VERSION 5.7 ;
  NOWIREEXTENSIONATPIN ON ;
  DIVIDERCHAR "/" ;
  BUSBITCHARS "[]" ;
MACRO INV_4_0_0_1653188215
  CLASS BLOCK ;
  FOREIGN INV_4_0_0_1653188215 ;
  ORIGIN 0.000 0.000 ;
  SIZE 5.415 BY 7.560 ;
  OBS
      LAYER nwell ;
        RECT 0.000 0.000 3.440 7.560 ;
      LAYER pwell ;
        RECT 4.515 6.030 4.945 7.410 ;
        RECT 4.045 2.180 5.415 3.490 ;
      LAYER li1 ;
        RECT 1.165 6.215 1.415 7.225 ;
        RECT 2.025 6.215 2.275 7.225 ;
        RECT 4.605 6.215 4.855 7.225 ;
        RECT 1.165 4.115 1.415 5.125 ;
        RECT 2.025 4.115 2.275 5.125 ;
        RECT 4.605 4.115 4.855 5.125 ;
        RECT 0.735 0.335 0.985 3.865 ;
        RECT 1.165 0.335 1.415 3.865 ;
        RECT 1.595 0.335 1.845 3.865 ;
        RECT 2.025 0.335 2.275 3.865 ;
        RECT 2.455 0.335 2.705 3.865 ;
        RECT 4.175 0.335 4.425 3.865 ;
        RECT 4.605 0.335 4.855 3.865 ;
        RECT 5.035 0.335 5.285 3.865 ;
      LAYER mcon ;
        RECT 1.205 6.635 1.375 6.805 ;
        RECT 2.065 6.635 2.235 6.805 ;
        RECT 4.645 6.635 4.815 6.805 ;
        RECT 1.205 4.535 1.375 4.705 ;
        RECT 2.065 4.535 2.235 4.705 ;
        RECT 4.645 4.535 4.815 4.705 ;
        RECT 0.775 0.755 0.945 0.925 ;
        RECT 1.205 0.335 1.375 0.505 ;
        RECT 1.635 0.755 1.805 0.925 ;
        RECT 2.065 0.335 2.235 0.505 ;
        RECT 2.495 0.755 2.665 0.925 ;
        RECT 4.215 0.755 4.385 0.925 ;
        RECT 4.645 0.335 4.815 0.505 ;
        RECT 5.075 0.755 5.245 0.925 ;
      LAYER met1 ;
        RECT 1.120 6.580 2.320 6.860 ;
        RECT 3.700 6.580 4.900 6.860 ;
        RECT 1.120 4.480 4.900 4.760 ;
        RECT 0.690 0.700 2.750 0.980 ;
        RECT 4.130 0.700 5.330 0.980 ;
        RECT 1.120 0.280 4.900 0.560 ;
  END
END INV_4_0_0_1653188215
MACRO INV_4_1_0_1653188216
  CLASS BLOCK ;
  FOREIGN INV_4_1_0_1653188216 ;
  ORIGIN 0.000 0.000 ;
  SIZE 5.415 BY 7.560 ;
  OBS
      LAYER nwell ;
        RECT 0.000 0.000 3.440 7.560 ;
      LAYER pwell ;
        RECT 4.515 6.030 4.945 7.410 ;
        RECT 4.045 2.180 5.415 3.490 ;
      LAYER li1 ;
        RECT 1.165 6.215 1.415 7.225 ;
        RECT 2.025 6.215 2.275 7.225 ;
        RECT 4.605 6.215 4.855 7.225 ;
        RECT 1.165 4.115 1.415 5.125 ;
        RECT 2.025 4.115 2.275 5.125 ;
        RECT 4.605 4.115 4.855 5.125 ;
        RECT 0.735 0.335 0.985 3.865 ;
        RECT 1.165 0.335 1.415 3.865 ;
        RECT 1.595 0.335 1.845 3.865 ;
        RECT 2.025 0.335 2.275 3.865 ;
        RECT 2.455 0.335 2.705 3.865 ;
        RECT 4.175 0.335 4.425 3.865 ;
        RECT 4.605 0.335 4.855 3.865 ;
        RECT 5.035 0.335 5.285 3.865 ;
      LAYER mcon ;
        RECT 1.205 6.635 1.375 6.805 ;
        RECT 2.065 6.635 2.235 6.805 ;
        RECT 4.645 6.635 4.815 6.805 ;
        RECT 1.205 4.535 1.375 4.705 ;
        RECT 2.065 4.535 2.235 4.705 ;
        RECT 4.645 4.535 4.815 4.705 ;
        RECT 0.775 0.755 0.945 0.925 ;
        RECT 1.205 0.335 1.375 0.505 ;
        RECT 1.635 0.755 1.805 0.925 ;
        RECT 2.065 0.335 2.235 0.505 ;
        RECT 2.495 0.755 2.665 0.925 ;
        RECT 4.215 0.755 4.385 0.925 ;
        RECT 4.645 0.335 4.815 0.505 ;
        RECT 5.075 0.755 5.245 0.925 ;
      LAYER met1 ;
        RECT 1.120 6.580 2.320 6.860 ;
        RECT 3.700 6.580 4.900 6.860 ;
        RECT 1.120 4.480 4.900 4.760 ;
        RECT 0.690 0.700 2.750 0.980 ;
        RECT 4.130 0.700 5.330 0.980 ;
        RECT 1.120 0.280 4.900 0.560 ;
  END
END INV_4_1_0_1653188216
MACRO DCDC_MUX_PMOS_0_0_1653188212
  CLASS BLOCK ;
  FOREIGN DCDC_MUX_PMOS_0_0_1653188212 ;
  ORIGIN 0.000 0.160 ;
  SIZE 8.600 BY 7.720 ;
  OBS
      LAYER nwell ;
        RECT 0.000 0.000 8.600 7.560 ;
      LAYER li1 ;
        RECT 1.165 6.215 1.415 7.225 ;
        RECT 2.025 6.215 2.275 7.225 ;
        RECT 2.885 6.215 3.135 7.225 ;
        RECT 5.465 6.215 5.715 7.225 ;
        RECT 6.325 6.215 6.575 7.225 ;
        RECT 7.185 6.215 7.435 7.225 ;
        RECT 1.165 4.115 1.415 5.125 ;
        RECT 2.025 4.115 2.275 5.125 ;
        RECT 2.885 4.115 3.135 5.125 ;
        RECT 5.465 4.115 5.715 5.125 ;
        RECT 6.325 4.115 6.575 5.125 ;
        RECT 7.185 4.115 7.435 5.125 ;
        RECT 0.735 0.335 0.985 3.865 ;
        RECT 1.165 0.335 1.415 3.865 ;
        RECT 1.595 0.335 1.845 3.865 ;
        RECT 2.025 0.335 2.275 3.865 ;
        RECT 2.455 0.335 2.705 3.865 ;
        RECT 2.885 0.335 3.135 3.865 ;
        RECT 3.315 0.335 3.565 3.865 ;
        RECT 4.175 0.335 4.425 0.925 ;
        RECT 5.035 0.335 5.285 3.865 ;
        RECT 5.465 0.335 5.715 3.865 ;
        RECT 5.895 0.335 6.145 3.865 ;
        RECT 6.325 0.335 6.575 3.865 ;
        RECT 6.755 0.335 7.005 3.865 ;
        RECT 7.185 0.335 7.435 3.865 ;
        RECT 7.615 0.335 7.865 3.865 ;
      LAYER mcon ;
        RECT 1.205 6.635 1.375 6.805 ;
        RECT 2.065 6.635 2.235 6.805 ;
        RECT 2.925 6.635 3.095 6.805 ;
        RECT 5.505 6.635 5.675 6.805 ;
        RECT 6.365 6.635 6.535 6.805 ;
        RECT 7.225 6.635 7.395 6.805 ;
        RECT 1.205 4.535 1.375 4.705 ;
        RECT 2.065 4.535 2.235 4.705 ;
        RECT 2.925 4.535 3.095 4.705 ;
        RECT 5.505 4.535 5.675 4.705 ;
        RECT 6.365 4.535 6.535 4.705 ;
        RECT 7.225 4.535 7.395 4.705 ;
        RECT 0.775 0.755 0.945 0.925 ;
        RECT 1.205 0.335 1.375 0.505 ;
        RECT 1.635 0.755 1.805 0.925 ;
        RECT 2.065 0.335 2.235 0.505 ;
        RECT 2.495 0.755 2.665 0.925 ;
        RECT 2.925 0.335 3.095 0.505 ;
        RECT 3.355 0.755 3.525 0.925 ;
        RECT 4.215 0.755 4.385 0.925 ;
        RECT 4.215 0.335 4.385 0.505 ;
        RECT 5.075 0.755 5.245 0.925 ;
        RECT 5.505 0.335 5.675 0.505 ;
        RECT 5.935 0.755 6.105 0.925 ;
        RECT 6.365 0.335 6.535 0.505 ;
        RECT 6.795 0.755 6.965 0.925 ;
        RECT 7.225 0.335 7.395 0.505 ;
        RECT 7.655 0.755 7.825 0.925 ;
      LAYER met1 ;
        RECT 1.120 6.580 7.480 6.860 ;
        RECT 1.120 4.480 3.180 4.760 ;
        RECT 5.420 4.480 7.480 4.760 ;
        RECT 0.690 0.700 4.470 0.980 ;
        RECT 4.990 0.700 7.910 0.980 ;
        RECT 1.120 0.280 3.600 0.560 ;
        RECT 4.130 0.280 7.480 0.560 ;
        RECT 3.280 -0.140 5.320 0.140 ;
      LAYER via ;
        RECT 5.030 0.710 5.290 0.970 ;
        RECT 3.310 0.290 3.570 0.550 ;
        RECT 3.310 -0.130 3.570 0.130 ;
        RECT 5.030 -0.130 5.290 0.130 ;
      LAYER met2 ;
        RECT 3.300 -0.160 3.580 0.580 ;
        RECT 5.020 -0.160 5.300 1.000 ;
  END
END DCDC_MUX_PMOS_0_0_1653188212
MACRO DCDC_MUX_TGATE_0_0_1653188213
  CLASS BLOCK ;
  FOREIGN DCDC_MUX_TGATE_0_0_1653188213 ;
  ORIGIN 0.000 -0.150 ;
  SIZE 4.300 BY 14.970 ;
  OBS
      LAYER nwell ;
        RECT 0.000 7.560 4.300 15.120 ;
      LAYER pwell ;
        RECT 0.605 4.070 3.695 5.380 ;
        RECT 1.075 0.150 3.225 1.530 ;
      LAYER li1 ;
        RECT 1.165 13.775 1.415 14.785 ;
        RECT 2.025 13.775 2.275 14.785 ;
        RECT 2.885 13.775 3.135 14.785 ;
        RECT 1.165 11.675 1.415 12.685 ;
        RECT 2.025 11.675 2.275 12.685 ;
        RECT 2.885 11.675 3.135 12.685 ;
        RECT 0.735 7.895 0.985 11.425 ;
        RECT 1.165 7.895 1.415 11.425 ;
        RECT 1.595 7.895 1.845 11.425 ;
        RECT 2.025 7.895 2.275 11.425 ;
        RECT 2.455 7.895 2.705 11.425 ;
        RECT 2.885 7.895 3.135 11.425 ;
        RECT 3.315 7.895 3.565 11.425 ;
        RECT 0.735 3.695 0.985 7.225 ;
        RECT 1.165 3.695 1.415 7.225 ;
        RECT 1.595 3.695 1.845 7.225 ;
        RECT 2.025 3.695 2.275 7.225 ;
        RECT 2.455 3.695 2.705 7.225 ;
        RECT 2.885 3.695 3.135 7.225 ;
        RECT 3.315 3.695 3.565 7.225 ;
        RECT 1.165 2.435 1.415 3.445 ;
        RECT 2.025 2.435 2.275 3.445 ;
        RECT 2.885 2.435 3.135 3.445 ;
        RECT 1.165 0.335 1.415 1.345 ;
        RECT 2.025 0.335 2.275 1.345 ;
        RECT 2.885 0.335 3.135 1.345 ;
      LAYER mcon ;
        RECT 1.205 14.195 1.375 14.365 ;
        RECT 2.065 14.195 2.235 14.365 ;
        RECT 2.925 14.195 3.095 14.365 ;
        RECT 1.205 12.095 1.375 12.265 ;
        RECT 2.065 12.095 2.235 12.265 ;
        RECT 2.925 12.095 3.095 12.265 ;
        RECT 0.775 8.315 0.945 8.485 ;
        RECT 1.205 7.895 1.375 8.065 ;
        RECT 1.635 8.315 1.805 8.485 ;
        RECT 2.065 7.895 2.235 8.065 ;
        RECT 2.495 8.315 2.665 8.485 ;
        RECT 2.925 7.895 3.095 8.065 ;
        RECT 3.355 8.315 3.525 8.485 ;
        RECT 0.775 6.635 0.945 6.805 ;
        RECT 1.205 7.055 1.375 7.225 ;
        RECT 1.635 6.635 1.805 6.805 ;
        RECT 2.065 7.055 2.235 7.225 ;
        RECT 2.495 6.635 2.665 6.805 ;
        RECT 2.925 7.055 3.095 7.225 ;
        RECT 3.355 6.635 3.525 6.805 ;
        RECT 1.205 2.855 1.375 3.025 ;
        RECT 2.065 2.855 2.235 3.025 ;
        RECT 2.925 2.855 3.095 3.025 ;
        RECT 1.205 0.755 1.375 0.925 ;
        RECT 2.065 0.755 2.235 0.925 ;
        RECT 2.925 0.755 3.095 0.925 ;
      LAYER met1 ;
        RECT 1.120 14.140 3.180 14.420 ;
        RECT 1.120 12.040 3.180 12.320 ;
        RECT 0.690 8.260 3.610 8.540 ;
        RECT 1.120 7.840 3.180 8.120 ;
        RECT 1.120 7.000 3.180 7.280 ;
        RECT 0.690 6.580 3.610 6.860 ;
        RECT 1.120 2.800 3.180 3.080 ;
        RECT 1.120 0.700 3.180 0.980 ;
      LAYER via ;
        RECT 1.590 8.270 1.850 8.530 ;
        RECT 2.020 7.850 2.280 8.110 ;
        RECT 2.020 7.010 2.280 7.270 ;
        RECT 1.590 6.590 1.850 6.850 ;
      LAYER met2 ;
        RECT 1.580 6.560 1.860 8.560 ;
        RECT 2.010 6.980 2.290 8.140 ;
  END
END DCDC_MUX_TGATE_0_0_1653188213
MACRO DCDC_MUX_TGATE_1_0_1653188214
  CLASS BLOCK ;
  FOREIGN DCDC_MUX_TGATE_1_0_1653188214 ;
  ORIGIN 0.000 -0.150 ;
  SIZE 4.300 BY 14.970 ;
  OBS
      LAYER nwell ;
        RECT 0.000 7.560 4.300 15.120 ;
      LAYER pwell ;
        RECT 0.605 4.070 3.695 5.380 ;
        RECT 1.075 0.150 3.225 1.530 ;
      LAYER li1 ;
        RECT 1.165 13.775 1.415 14.785 ;
        RECT 2.025 13.775 2.275 14.785 ;
        RECT 2.885 13.775 3.135 14.785 ;
        RECT 1.165 11.675 1.415 12.685 ;
        RECT 2.025 11.675 2.275 12.685 ;
        RECT 2.885 11.675 3.135 12.685 ;
        RECT 0.735 7.895 0.985 11.425 ;
        RECT 1.165 7.895 1.415 11.425 ;
        RECT 1.595 7.895 1.845 11.425 ;
        RECT 2.025 7.895 2.275 11.425 ;
        RECT 2.455 7.895 2.705 11.425 ;
        RECT 2.885 7.895 3.135 11.425 ;
        RECT 3.315 7.895 3.565 11.425 ;
        RECT 0.735 3.695 0.985 7.225 ;
        RECT 1.165 3.695 1.415 7.225 ;
        RECT 1.595 3.695 1.845 7.225 ;
        RECT 2.025 3.695 2.275 7.225 ;
        RECT 2.455 3.695 2.705 7.225 ;
        RECT 2.885 3.695 3.135 7.225 ;
        RECT 3.315 3.695 3.565 7.225 ;
        RECT 1.165 2.435 1.415 3.445 ;
        RECT 2.025 2.435 2.275 3.445 ;
        RECT 2.885 2.435 3.135 3.445 ;
        RECT 1.165 0.335 1.415 1.345 ;
        RECT 2.025 0.335 2.275 1.345 ;
        RECT 2.885 0.335 3.135 1.345 ;
      LAYER mcon ;
        RECT 1.205 14.195 1.375 14.365 ;
        RECT 2.065 14.195 2.235 14.365 ;
        RECT 2.925 14.195 3.095 14.365 ;
        RECT 1.205 12.095 1.375 12.265 ;
        RECT 2.065 12.095 2.235 12.265 ;
        RECT 2.925 12.095 3.095 12.265 ;
        RECT 0.775 8.315 0.945 8.485 ;
        RECT 1.205 7.895 1.375 8.065 ;
        RECT 1.635 8.315 1.805 8.485 ;
        RECT 2.065 7.895 2.235 8.065 ;
        RECT 2.495 8.315 2.665 8.485 ;
        RECT 2.925 7.895 3.095 8.065 ;
        RECT 3.355 8.315 3.525 8.485 ;
        RECT 0.775 6.635 0.945 6.805 ;
        RECT 1.205 7.055 1.375 7.225 ;
        RECT 1.635 6.635 1.805 6.805 ;
        RECT 2.065 7.055 2.235 7.225 ;
        RECT 2.495 6.635 2.665 6.805 ;
        RECT 2.925 7.055 3.095 7.225 ;
        RECT 3.355 6.635 3.525 6.805 ;
        RECT 1.205 2.855 1.375 3.025 ;
        RECT 2.065 2.855 2.235 3.025 ;
        RECT 2.925 2.855 3.095 3.025 ;
        RECT 1.205 0.755 1.375 0.925 ;
        RECT 2.065 0.755 2.235 0.925 ;
        RECT 2.925 0.755 3.095 0.925 ;
      LAYER met1 ;
        RECT 1.120 14.140 3.180 14.420 ;
        RECT 1.120 12.040 3.180 12.320 ;
        RECT 0.690 8.260 3.610 8.540 ;
        RECT 1.120 7.840 3.180 8.120 ;
        RECT 1.120 7.000 3.180 7.280 ;
        RECT 0.690 6.580 3.610 6.860 ;
        RECT 1.120 2.800 3.180 3.080 ;
        RECT 1.120 0.700 3.180 0.980 ;
      LAYER via ;
        RECT 2.450 8.270 2.710 8.530 ;
        RECT 2.020 7.850 2.280 8.110 ;
        RECT 2.020 7.010 2.280 7.270 ;
        RECT 2.450 6.590 2.710 6.850 ;
      LAYER met2 ;
        RECT 2.010 6.980 2.290 8.140 ;
        RECT 2.440 6.560 2.720 8.560 ;
  END
END DCDC_MUX_TGATE_1_0_1653188214
MACRO DCDC_MUX_NMOS_0_0_1653188211
  CLASS BLOCK ;
  FOREIGN DCDC_MUX_NMOS_0_0_1653188211 ;
  ORIGIN -0.605 -0.260 ;
  SIZE 7.390 BY 7.150 ;
  OBS
      LAYER pwell ;
        RECT 1.075 6.030 3.225 7.410 ;
        RECT 5.375 6.030 7.525 7.410 ;
        RECT 0.605 2.180 3.695 3.490 ;
        RECT 4.905 2.180 7.995 3.490 ;
      LAYER li1 ;
        RECT 1.165 6.215 1.415 7.225 ;
        RECT 2.025 6.215 2.275 7.225 ;
        RECT 2.885 6.215 3.135 7.225 ;
        RECT 5.465 6.215 5.715 7.225 ;
        RECT 6.325 6.215 6.575 7.225 ;
        RECT 7.185 6.215 7.435 7.225 ;
        RECT 1.165 4.115 1.415 5.125 ;
        RECT 2.025 4.115 2.275 5.125 ;
        RECT 2.885 4.115 3.135 5.125 ;
        RECT 5.465 4.115 5.715 5.125 ;
        RECT 6.325 4.115 6.575 5.125 ;
        RECT 7.185 4.115 7.435 5.125 ;
        RECT 0.735 0.335 0.985 3.865 ;
        RECT 1.165 0.335 1.415 3.865 ;
        RECT 1.595 0.335 1.845 3.865 ;
        RECT 2.025 0.335 2.275 3.865 ;
        RECT 2.455 0.335 2.705 3.865 ;
        RECT 2.885 0.335 3.135 3.865 ;
        RECT 3.315 0.335 3.565 3.865 ;
        RECT 4.175 0.335 4.425 0.925 ;
        RECT 5.035 0.335 5.285 3.865 ;
        RECT 5.465 0.335 5.715 3.865 ;
        RECT 5.895 0.335 6.145 3.865 ;
        RECT 6.325 0.335 6.575 3.865 ;
        RECT 6.755 0.335 7.005 3.865 ;
        RECT 7.185 0.335 7.435 3.865 ;
        RECT 7.615 0.335 7.865 3.865 ;
      LAYER mcon ;
        RECT 1.205 6.635 1.375 6.805 ;
        RECT 2.065 6.635 2.235 6.805 ;
        RECT 2.925 6.635 3.095 6.805 ;
        RECT 5.505 6.635 5.675 6.805 ;
        RECT 6.365 6.635 6.535 6.805 ;
        RECT 7.225 6.635 7.395 6.805 ;
        RECT 1.205 4.535 1.375 4.705 ;
        RECT 2.065 4.535 2.235 4.705 ;
        RECT 2.925 4.535 3.095 4.705 ;
        RECT 5.505 4.535 5.675 4.705 ;
        RECT 6.365 4.535 6.535 4.705 ;
        RECT 7.225 4.535 7.395 4.705 ;
        RECT 0.775 0.755 0.945 0.925 ;
        RECT 1.205 0.335 1.375 0.505 ;
        RECT 1.635 0.755 1.805 0.925 ;
        RECT 2.065 0.335 2.235 0.505 ;
        RECT 2.495 0.755 2.665 0.925 ;
        RECT 2.925 0.335 3.095 0.505 ;
        RECT 3.355 0.755 3.525 0.925 ;
        RECT 4.215 0.755 4.385 0.925 ;
        RECT 4.215 0.335 4.385 0.505 ;
        RECT 5.075 0.755 5.245 0.925 ;
        RECT 5.505 0.335 5.675 0.505 ;
        RECT 5.935 0.755 6.105 0.925 ;
        RECT 6.365 0.335 6.535 0.505 ;
        RECT 6.795 0.755 6.965 0.925 ;
        RECT 7.225 0.335 7.395 0.505 ;
        RECT 7.655 0.755 7.825 0.925 ;
      LAYER met1 ;
        RECT 1.120 6.580 7.480 6.860 ;
        RECT 1.120 4.480 3.180 4.760 ;
        RECT 5.420 4.480 7.480 4.760 ;
        RECT 3.280 1.120 5.320 1.400 ;
        RECT 0.690 0.700 4.470 0.980 ;
        RECT 4.990 0.700 7.910 0.980 ;
        RECT 1.120 0.280 3.600 0.560 ;
        RECT 4.130 0.280 7.480 0.560 ;
      LAYER via ;
        RECT 3.310 1.130 3.570 1.390 ;
        RECT 5.030 1.130 5.290 1.390 ;
        RECT 5.030 0.710 5.290 0.970 ;
        RECT 3.310 0.290 3.570 0.550 ;
      LAYER met2 ;
        RECT 3.300 0.260 3.580 1.420 ;
        RECT 5.020 0.680 5.300 1.420 ;
  END
END DCDC_MUX_NMOS_0_0_1653188211
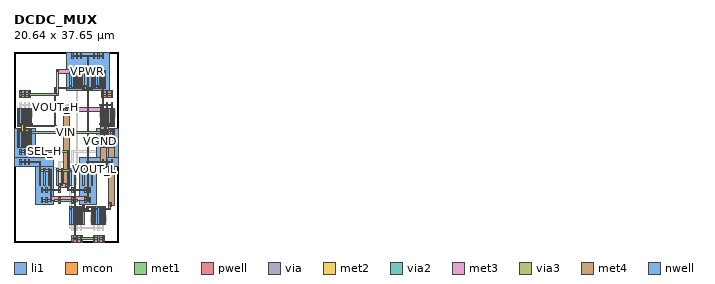
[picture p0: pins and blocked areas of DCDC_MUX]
MACRO DCDC_MUX
  CLASS BLOCK ;
  FOREIGN DCDC_MUX ;
  ORIGIN 0.000 -0.150 ;
  SIZE 20.640 BY 37.650 ;
  PIN SEL_H
    ANTENNAGATEAREA 1.890000 ;
    PORT
      LAYER li1 ;
        RECT 1.165 17.555 1.415 18.565 ;
        RECT 2.025 17.555 2.275 18.565 ;
        RECT 2.885 17.555 3.135 18.565 ;
        RECT 10.625 10.415 10.875 18.145 ;
        RECT 11.485 9.995 11.735 11.005 ;
        RECT 14.065 9.995 14.315 11.005 ;
        RECT 14.925 9.995 15.175 11.005 ;
      LAYER mcon ;
        RECT 1.205 17.975 1.375 18.145 ;
        RECT 2.065 17.975 2.235 18.145 ;
        RECT 2.925 17.975 3.095 18.145 ;
        RECT 10.665 17.975 10.835 18.145 ;
        RECT 10.665 10.415 10.835 10.585 ;
        RECT 11.525 10.415 11.695 10.585 ;
        RECT 14.105 10.415 14.275 10.585 ;
        RECT 14.965 10.415 15.135 10.585 ;
      LAYER met1 ;
        RECT 1.120 17.920 10.920 18.200 ;
        RECT 10.580 10.360 15.220 10.640 ;
    END
  END SEL_H
  PIN VGND
    USE GROUND ;
    PORT
      LAYER pwell ;
        RECT 1.075 28.710 3.225 30.090 ;
        RECT 17.415 28.710 19.565 30.090 ;
        RECT 8.815 7.710 9.245 9.090 ;
        RECT 11.395 7.710 11.825 9.090 ;
        RECT 11.395 0.150 13.545 1.530 ;
        RECT 15.695 0.150 17.845 1.530 ;
      LAYER li1 ;
        RECT 1.165 28.895 1.415 29.905 ;
        RECT 2.025 28.895 2.275 29.905 ;
        RECT 2.885 28.895 3.135 29.905 ;
        RECT 17.505 28.895 17.755 29.905 ;
        RECT 18.365 28.895 18.615 29.905 ;
        RECT 19.225 28.895 19.475 29.905 ;
        RECT 8.475 11.255 8.725 14.785 ;
        RECT 9.335 11.255 9.585 14.785 ;
        RECT 11.055 11.255 11.305 14.785 ;
        RECT 11.915 11.255 12.165 14.785 ;
        RECT 8.905 7.895 9.155 8.905 ;
        RECT 11.485 7.895 11.735 8.905 ;
        RECT 11.055 3.695 11.305 7.225 ;
        RECT 11.915 3.695 12.165 7.225 ;
        RECT 12.775 3.695 13.025 7.225 ;
        RECT 13.635 3.695 13.885 7.225 ;
        RECT 14.495 6.635 14.745 7.225 ;
        RECT 15.785 3.695 16.035 7.225 ;
        RECT 16.645 3.695 16.895 7.225 ;
        RECT 17.505 3.695 17.755 7.225 ;
        RECT 11.485 0.335 11.735 1.345 ;
        RECT 12.345 0.335 12.595 1.345 ;
        RECT 13.205 0.335 13.455 1.345 ;
        RECT 15.785 0.335 16.035 1.345 ;
        RECT 16.645 0.335 16.895 1.345 ;
        RECT 17.505 0.335 17.755 1.345 ;
      LAYER mcon ;
        RECT 1.205 29.315 1.375 29.485 ;
        RECT 2.065 29.315 2.235 29.485 ;
        RECT 2.925 29.315 3.095 29.485 ;
        RECT 17.545 29.315 17.715 29.485 ;
        RECT 18.405 29.315 18.575 29.485 ;
        RECT 19.265 29.315 19.435 29.485 ;
        RECT 8.515 14.195 8.685 14.365 ;
        RECT 9.375 14.195 9.545 14.365 ;
        RECT 11.095 14.195 11.265 14.365 ;
        RECT 11.955 14.195 12.125 14.365 ;
        RECT 8.945 8.315 9.115 8.485 ;
        RECT 11.525 8.315 11.695 8.485 ;
        RECT 11.095 6.635 11.265 6.805 ;
        RECT 11.955 6.635 12.125 6.805 ;
        RECT 12.815 6.635 12.985 6.805 ;
        RECT 13.675 6.635 13.845 6.805 ;
        RECT 14.535 7.055 14.705 7.225 ;
        RECT 14.535 6.635 14.705 6.805 ;
        RECT 15.825 7.055 15.995 7.225 ;
        RECT 16.685 7.055 16.855 7.225 ;
        RECT 17.545 7.055 17.715 7.225 ;
        RECT 11.525 0.755 11.695 0.925 ;
        RECT 12.385 0.755 12.555 0.925 ;
        RECT 13.245 0.755 13.415 0.925 ;
        RECT 15.825 0.755 15.995 0.925 ;
        RECT 16.685 0.755 16.855 0.925 ;
        RECT 17.545 0.755 17.715 0.925 ;
      LAYER met1 ;
        RECT 1.120 29.260 8.760 29.540 ;
        RECT 17.460 29.260 19.520 29.540 ;
        RECT 8.430 14.140 12.210 14.420 ;
        RECT 8.000 8.260 12.640 8.540 ;
        RECT 14.450 7.000 17.800 7.280 ;
        RECT 11.010 6.580 14.790 6.860 ;
        RECT 11.440 0.700 17.800 0.980 ;
      LAYER via ;
        RECT 8.470 29.270 8.730 29.530 ;
        RECT 17.500 29.270 17.760 29.530 ;
        RECT 11.910 14.150 12.170 14.410 ;
        RECT 11.910 8.270 12.170 8.530 ;
        RECT 11.910 6.590 12.170 6.850 ;
        RECT 11.910 0.710 12.170 0.970 ;
      LAYER met2 ;
        RECT 8.460 29.240 8.740 34.205 ;
        RECT 17.490 25.015 17.770 34.205 ;
        RECT 11.900 0.680 12.180 15.305 ;
      LAYER via2 ;
        RECT 8.460 33.880 8.740 34.160 ;
        RECT 17.490 33.880 17.770 34.160 ;
        RECT 17.490 25.060 17.770 25.340 ;
        RECT 11.900 14.980 12.180 15.260 ;
      LAYER met3 ;
        RECT 8.435 33.620 17.795 34.420 ;
        RECT 17.465 24.800 17.925 25.600 ;
        RECT 11.875 14.720 17.925 15.520 ;
      LAYER via3 ;
        RECT 17.600 25.040 17.920 25.360 ;
        RECT 17.600 14.960 17.920 15.280 ;
      LAYER met4 ;
        RECT 17.170 14.955 18.350 25.365 ;
    END
  END VGND
  PIN VPWR
    USE POWER ;
    PORT
      LAYER nwell ;
        RECT 10.320 30.240 18.920 37.800 ;
        RECT 0.000 16.800 4.300 22.680 ;
        RECT 16.340 16.800 20.640 22.680 ;
        RECT 0.000 15.120 7.740 16.800 ;
        RECT 4.300 7.560 7.740 15.120 ;
        RECT 12.900 15.120 20.640 16.800 ;
        RECT 12.900 7.560 16.340 15.120 ;
      LAYER li1 ;
        RECT 11.485 36.455 11.735 37.465 ;
        RECT 12.345 36.455 12.595 37.465 ;
        RECT 13.205 36.455 13.455 37.465 ;
        RECT 11.055 30.575 11.305 34.105 ;
        RECT 11.915 30.575 12.165 34.105 ;
        RECT 12.775 30.575 13.025 34.105 ;
        RECT 13.635 30.575 13.885 34.105 ;
        RECT 1.165 15.455 1.415 16.465 ;
        RECT 2.025 15.455 2.275 16.465 ;
        RECT 2.885 15.455 3.135 16.465 ;
        RECT 14.495 15.035 14.745 37.045 ;
        RECT 15.785 36.455 16.035 37.465 ;
        RECT 16.645 36.455 16.895 37.465 ;
        RECT 17.505 36.455 17.755 37.465 ;
        RECT 15.785 30.575 16.035 34.105 ;
        RECT 16.645 30.575 16.895 34.105 ;
        RECT 17.505 30.575 17.755 34.105 ;
        RECT 17.505 15.455 17.755 16.465 ;
        RECT 18.365 15.455 18.615 16.465 ;
        RECT 19.225 15.455 19.475 16.465 ;
        RECT 5.035 11.255 5.285 14.785 ;
        RECT 5.895 11.255 6.145 14.785 ;
        RECT 6.755 11.255 7.005 14.785 ;
        RECT 13.635 11.255 13.885 14.785 ;
        RECT 14.495 11.255 14.745 14.785 ;
        RECT 15.355 11.255 15.605 14.785 ;
        RECT 5.465 7.895 5.715 8.905 ;
        RECT 6.325 7.895 6.575 8.905 ;
        RECT 14.065 7.895 14.315 8.905 ;
        RECT 14.925 7.895 15.175 8.905 ;
      LAYER mcon ;
        RECT 11.525 36.875 11.695 37.045 ;
        RECT 12.385 36.875 12.555 37.045 ;
        RECT 13.245 36.875 13.415 37.045 ;
        RECT 14.535 36.875 14.705 37.045 ;
        RECT 11.095 30.995 11.265 31.165 ;
        RECT 11.955 30.995 12.125 31.165 ;
        RECT 12.815 30.995 12.985 31.165 ;
        RECT 13.675 30.995 13.845 31.165 ;
        RECT 15.825 36.875 15.995 37.045 ;
        RECT 16.685 36.875 16.855 37.045 ;
        RECT 17.545 36.875 17.715 37.045 ;
        RECT 14.535 30.995 14.705 31.165 ;
        RECT 14.535 30.575 14.705 30.745 ;
        RECT 15.825 30.575 15.995 30.745 ;
        RECT 16.685 30.575 16.855 30.745 ;
        RECT 17.545 30.575 17.715 30.745 ;
        RECT 1.205 15.875 1.375 16.045 ;
        RECT 2.065 15.875 2.235 16.045 ;
        RECT 2.925 15.875 3.095 16.045 ;
        RECT 14.535 15.875 14.705 16.045 ;
        RECT 17.545 15.875 17.715 16.045 ;
        RECT 18.405 15.875 18.575 16.045 ;
        RECT 19.265 15.875 19.435 16.045 ;
        RECT 14.535 15.035 14.705 15.205 ;
        RECT 5.075 14.195 5.245 14.365 ;
        RECT 5.935 14.195 6.105 14.365 ;
        RECT 6.795 14.195 6.965 14.365 ;
        RECT 13.675 14.195 13.845 14.365 ;
        RECT 14.535 14.195 14.705 14.365 ;
        RECT 15.395 14.195 15.565 14.365 ;
        RECT 5.505 8.315 5.675 8.485 ;
        RECT 6.365 8.315 6.535 8.485 ;
        RECT 14.105 8.315 14.275 8.485 ;
        RECT 14.965 8.315 15.135 8.485 ;
      LAYER met1 ;
        RECT 11.440 36.820 17.800 37.100 ;
        RECT 11.010 30.940 14.790 31.220 ;
        RECT 14.450 30.520 17.800 30.800 ;
        RECT 1.120 15.820 5.320 16.100 ;
        RECT 14.450 15.820 19.520 16.100 ;
        RECT 14.450 14.980 14.790 15.260 ;
        RECT 4.990 14.140 7.470 14.420 ;
        RECT 13.590 14.140 15.650 14.420 ;
        RECT 5.420 8.260 7.470 8.540 ;
        RECT 14.020 8.260 15.220 8.540 ;
      LAYER via ;
        RECT 5.030 15.830 5.290 16.090 ;
        RECT 14.490 14.990 14.750 15.250 ;
        RECT 5.030 14.150 5.290 14.410 ;
        RECT 7.180 14.150 7.440 14.410 ;
        RECT 14.490 14.150 14.750 14.410 ;
        RECT 7.180 8.270 7.440 8.530 ;
        RECT 14.490 8.270 14.750 8.530 ;
      LAYER met2 ;
        RECT 5.020 14.120 5.300 16.120 ;
        RECT 7.170 8.240 7.450 14.440 ;
        RECT 14.480 8.240 14.760 15.280 ;
      LAYER via2 ;
        RECT 7.170 8.680 7.450 8.960 ;
        RECT 14.480 8.680 14.760 8.960 ;
      LAYER met3 ;
        RECT 7.145 8.420 14.785 9.220 ;
    END
  END VPWR
  PIN SEL_L
    ANTENNAGATEAREA 1.890000 ;
    PORT
      LAYER li1 ;
        RECT 17.505 26.795 17.755 27.805 ;
        RECT 18.365 26.795 18.615 27.805 ;
        RECT 19.225 26.795 19.475 27.805 ;
        RECT 5.465 9.995 5.715 11.005 ;
        RECT 6.325 9.995 6.575 11.005 ;
        RECT 8.905 9.995 9.155 11.005 ;
      LAYER mcon ;
        RECT 17.545 27.215 17.715 27.385 ;
        RECT 18.405 27.215 18.575 27.385 ;
        RECT 19.265 27.215 19.435 27.385 ;
        RECT 5.505 10.415 5.675 10.585 ;
        RECT 6.365 10.415 6.535 10.585 ;
        RECT 8.945 10.415 9.115 10.585 ;
      LAYER met1 ;
        RECT 17.040 27.160 19.520 27.440 ;
        RECT 5.420 10.360 9.200 10.640 ;
      LAYER via ;
        RECT 17.070 27.170 17.330 27.430 ;
        RECT 8.900 10.370 9.160 10.630 ;
      LAYER met2 ;
        RECT 17.060 26.275 17.340 27.460 ;
        RECT 8.890 10.340 9.170 11.525 ;
      LAYER via2 ;
        RECT 17.060 26.320 17.340 26.600 ;
        RECT 8.890 11.200 9.170 11.480 ;
      LAYER met3 ;
        RECT 10.195 26.060 17.365 26.860 ;
        RECT 8.865 10.940 10.525 11.740 ;
      LAYER via3 ;
        RECT 10.200 26.300 10.520 26.620 ;
        RECT 10.200 11.180 10.520 11.500 ;
      LAYER met4 ;
        RECT 9.770 11.175 10.950 26.625 ;
    END
  END SEL_L
  PIN VOUT_H
    ANTENNADIFFAREA 3.790500 ;
    PORT
      LAYER li1 ;
        RECT 11.485 30.575 11.735 34.105 ;
        RECT 12.345 30.575 12.595 34.105 ;
        RECT 13.205 30.575 13.455 34.105 ;
        RECT 15.355 30.575 15.605 34.105 ;
        RECT 16.215 30.575 16.465 34.105 ;
        RECT 17.075 30.575 17.325 34.105 ;
        RECT 17.935 30.575 18.185 34.105 ;
        RECT 1.165 23.015 1.415 26.545 ;
        RECT 2.025 23.015 2.275 26.545 ;
        RECT 2.885 23.015 3.135 26.545 ;
        RECT 1.165 18.815 1.415 22.345 ;
        RECT 2.025 18.815 2.275 22.345 ;
        RECT 2.885 18.815 3.135 22.345 ;
      LAYER mcon ;
        RECT 11.525 30.575 11.695 30.745 ;
        RECT 12.385 30.575 12.555 30.745 ;
        RECT 13.245 30.575 13.415 30.745 ;
        RECT 15.395 30.995 15.565 31.165 ;
        RECT 16.255 30.995 16.425 31.165 ;
        RECT 17.115 30.995 17.285 31.165 ;
        RECT 17.975 30.995 18.145 31.165 ;
        RECT 1.205 23.015 1.375 23.185 ;
        RECT 2.065 23.015 2.235 23.185 ;
        RECT 2.925 23.015 3.095 23.185 ;
        RECT 1.205 22.175 1.375 22.345 ;
        RECT 2.065 22.175 2.235 22.345 ;
        RECT 2.925 22.175 3.095 22.345 ;
      LAYER met1 ;
        RECT 15.310 30.940 18.230 31.220 ;
        RECT 8.010 30.520 13.920 30.800 ;
        RECT 13.600 30.100 15.640 30.380 ;
        RECT 1.120 22.960 8.330 23.240 ;
        RECT 1.120 22.120 3.180 22.400 ;
      LAYER via ;
        RECT 15.350 30.950 15.610 31.210 ;
        RECT 8.040 30.530 8.300 30.790 ;
        RECT 13.630 30.530 13.890 30.790 ;
        RECT 13.630 30.110 13.890 30.370 ;
        RECT 15.350 30.110 15.610 30.370 ;
        RECT 2.020 22.970 2.280 23.230 ;
        RECT 8.040 22.970 8.300 23.230 ;
        RECT 2.020 22.130 2.280 22.390 ;
      LAYER met2 ;
        RECT 2.010 22.100 2.290 23.260 ;
        RECT 8.030 22.940 8.310 30.820 ;
        RECT 13.620 30.080 13.900 30.820 ;
        RECT 15.340 30.080 15.620 31.240 ;
    END
  END VOUT_H
  PIN VIN
    ANTENNADIFFAREA 4.578000 ;
    PORT
      LAYER li1 ;
        RECT 0.735 23.015 0.985 26.545 ;
        RECT 1.595 23.015 1.845 26.545 ;
        RECT 2.455 23.015 2.705 26.545 ;
        RECT 3.315 23.015 3.565 26.545 ;
        RECT 17.075 23.015 17.325 26.545 ;
        RECT 17.935 23.015 18.185 26.545 ;
        RECT 18.795 23.015 19.045 26.545 ;
        RECT 19.655 23.015 19.905 26.545 ;
        RECT 0.735 18.815 0.985 22.345 ;
        RECT 1.595 18.815 1.845 22.345 ;
        RECT 2.455 18.815 2.705 22.345 ;
        RECT 3.315 18.815 3.565 22.345 ;
        RECT 17.075 18.815 17.325 22.345 ;
        RECT 17.935 18.815 18.185 22.345 ;
        RECT 18.795 18.815 19.045 22.345 ;
        RECT 19.655 18.815 19.905 22.345 ;
      LAYER mcon ;
        RECT 0.775 23.435 0.945 23.605 ;
        RECT 1.635 23.435 1.805 23.605 ;
        RECT 2.495 23.435 2.665 23.605 ;
        RECT 3.355 23.435 3.525 23.605 ;
        RECT 17.115 23.435 17.285 23.605 ;
        RECT 17.975 23.435 18.145 23.605 ;
        RECT 18.835 23.435 19.005 23.605 ;
        RECT 19.695 23.435 19.865 23.605 ;
        RECT 0.775 21.755 0.945 21.925 ;
        RECT 1.635 21.755 1.805 21.925 ;
        RECT 2.495 21.755 2.665 21.925 ;
        RECT 3.355 21.755 3.525 21.925 ;
        RECT 17.115 21.755 17.285 21.925 ;
        RECT 17.975 21.755 18.145 21.925 ;
        RECT 18.835 21.755 19.005 21.925 ;
        RECT 19.695 21.755 19.865 21.925 ;
      LAYER met1 ;
        RECT 0.690 23.380 3.610 23.660 ;
        RECT 17.030 23.380 19.950 23.660 ;
        RECT 0.690 21.700 19.950 21.980 ;
      LAYER via ;
        RECT 1.590 23.390 1.850 23.650 ;
        RECT 17.930 23.390 18.190 23.650 ;
        RECT 1.590 21.710 1.850 21.970 ;
        RECT 17.930 21.710 18.190 21.970 ;
      LAYER met2 ;
        RECT 1.580 21.680 1.860 23.680 ;
        RECT 17.920 21.680 18.200 23.680 ;
    END
  END VIN
  PIN VOUT_L
    ANTENNADIFFAREA 3.790500 ;
    PORT
      LAYER li1 ;
        RECT 17.505 23.015 17.755 26.545 ;
        RECT 18.365 23.015 18.615 26.545 ;
        RECT 19.225 23.015 19.475 26.545 ;
        RECT 17.505 18.815 17.755 22.345 ;
        RECT 18.365 18.815 18.615 22.345 ;
        RECT 19.225 18.815 19.475 22.345 ;
        RECT 11.485 3.695 11.735 7.225 ;
        RECT 12.345 3.695 12.595 7.225 ;
        RECT 13.205 3.695 13.455 7.225 ;
        RECT 15.355 3.695 15.605 7.225 ;
        RECT 16.215 3.695 16.465 7.225 ;
        RECT 17.075 3.695 17.325 7.225 ;
        RECT 17.935 3.695 18.185 7.225 ;
      LAYER mcon ;
        RECT 17.545 23.015 17.715 23.185 ;
        RECT 18.405 23.015 18.575 23.185 ;
        RECT 19.265 23.015 19.435 23.185 ;
        RECT 17.545 22.175 17.715 22.345 ;
        RECT 18.405 22.175 18.575 22.345 ;
        RECT 19.265 22.175 19.435 22.345 ;
        RECT 11.525 7.055 11.695 7.225 ;
        RECT 12.385 7.055 12.555 7.225 ;
        RECT 13.245 7.055 13.415 7.225 ;
        RECT 15.395 6.635 15.565 6.805 ;
        RECT 16.255 6.635 16.425 6.805 ;
        RECT 17.115 6.635 17.285 6.805 ;
        RECT 17.975 6.635 18.145 6.805 ;
      LAYER met1 ;
        RECT 17.460 22.960 19.520 23.240 ;
        RECT 17.460 22.120 19.520 22.400 ;
        RECT 11.440 7.000 13.920 7.280 ;
        RECT 15.310 6.580 19.080 6.860 ;
        RECT 13.600 6.160 15.640 6.440 ;
      LAYER via ;
        RECT 18.360 22.970 18.620 23.230 ;
        RECT 18.360 22.130 18.620 22.390 ;
        RECT 19.220 22.130 19.480 22.390 ;
        RECT 13.630 7.010 13.890 7.270 ;
        RECT 15.350 6.590 15.610 6.850 ;
        RECT 18.790 6.590 19.050 6.850 ;
        RECT 13.630 6.170 13.890 6.430 ;
        RECT 15.350 6.170 15.610 6.430 ;
      LAYER met2 ;
        RECT 18.350 22.100 18.630 23.260 ;
        RECT 19.210 21.235 19.490 22.420 ;
        RECT 13.620 6.140 13.900 7.300 ;
        RECT 15.340 6.140 15.620 6.880 ;
        RECT 18.780 6.560 19.060 7.745 ;
      LAYER via2 ;
        RECT 19.210 21.280 19.490 21.560 ;
        RECT 18.780 7.420 19.060 7.700 ;
      LAYER met3 ;
        RECT 19.075 21.020 19.515 21.820 ;
        RECT 18.755 7.160 19.405 7.960 ;
      LAYER via3 ;
        RECT 19.080 21.260 19.400 21.580 ;
        RECT 19.080 7.400 19.400 7.720 ;
      LAYER met4 ;
        RECT 18.650 7.395 19.830 21.585 ;
    END
  END VOUT_L
  OBS
      LAYER pwell ;
        RECT 0.605 24.860 3.695 26.170 ;
        RECT 16.945 24.860 20.035 26.170 ;
        RECT 8.345 11.630 9.715 12.940 ;
        RECT 10.925 11.630 12.295 12.940 ;
        RECT 10.925 4.070 14.015 5.380 ;
        RECT 15.225 4.070 18.315 5.380 ;
      LAYER li1 ;
        RECT 11.485 34.355 11.735 35.365 ;
        RECT 12.345 34.355 12.595 35.365 ;
        RECT 13.205 34.355 13.455 35.365 ;
        RECT 15.785 34.355 16.035 35.365 ;
        RECT 16.645 34.355 16.895 35.365 ;
        RECT 17.505 34.355 17.755 35.365 ;
        RECT 1.165 26.795 1.415 27.805 ;
        RECT 2.025 26.795 2.275 27.805 ;
        RECT 2.885 26.795 3.135 27.805 ;
        RECT 5.465 11.255 5.715 14.785 ;
        RECT 6.325 11.255 6.575 14.785 ;
        RECT 8.905 11.255 9.155 14.785 ;
        RECT 11.485 11.255 11.735 14.785 ;
        RECT 12.345 14.615 12.595 25.285 ;
        RECT 17.505 17.555 17.755 18.565 ;
        RECT 18.365 17.555 18.615 18.565 ;
        RECT 19.225 17.555 19.475 18.565 ;
        RECT 14.065 11.255 14.315 14.785 ;
        RECT 14.925 11.255 15.175 14.785 ;
        RECT 11.485 2.435 11.735 3.445 ;
        RECT 12.345 2.435 12.595 3.445 ;
        RECT 13.205 2.435 13.455 3.445 ;
        RECT 15.785 2.435 16.035 3.445 ;
        RECT 16.645 2.435 16.895 3.445 ;
        RECT 17.505 2.435 17.755 3.445 ;
      LAYER mcon ;
        RECT 11.525 34.775 11.695 34.945 ;
        RECT 12.385 34.775 12.555 34.945 ;
        RECT 13.245 34.775 13.415 34.945 ;
        RECT 15.825 34.775 15.995 34.945 ;
        RECT 16.685 34.775 16.855 34.945 ;
        RECT 17.545 34.775 17.715 34.945 ;
        RECT 1.205 27.215 1.375 27.385 ;
        RECT 2.065 27.215 2.235 27.385 ;
        RECT 2.925 27.215 3.095 27.385 ;
        RECT 12.385 25.115 12.555 25.285 ;
        RECT 17.545 17.975 17.715 18.145 ;
        RECT 18.405 17.975 18.575 18.145 ;
        RECT 19.265 17.975 19.435 18.145 ;
        RECT 5.505 14.615 5.675 14.785 ;
        RECT 6.365 14.615 6.535 14.785 ;
        RECT 8.945 14.615 9.115 14.785 ;
        RECT 11.525 14.615 11.695 14.785 ;
        RECT 12.385 14.615 12.555 14.785 ;
        RECT 14.105 14.615 14.275 14.785 ;
        RECT 14.965 14.615 15.135 14.785 ;
        RECT 11.525 2.855 11.695 3.025 ;
        RECT 12.385 2.855 12.555 3.025 ;
        RECT 13.245 2.855 13.415 3.025 ;
        RECT 15.825 2.855 15.995 3.025 ;
        RECT 16.685 2.855 16.855 3.025 ;
        RECT 17.545 2.855 17.715 3.025 ;
      LAYER met1 ;
        RECT 11.440 34.720 17.800 35.000 ;
        RECT 1.120 27.160 12.630 27.440 ;
        RECT 12.300 25.060 12.640 25.340 ;
        RECT 11.450 17.920 19.520 18.200 ;
        RECT 8.870 15.820 11.770 16.100 ;
        RECT 5.420 14.560 9.200 14.840 ;
        RECT 11.440 14.560 15.220 14.840 ;
        RECT 11.020 2.800 17.800 3.080 ;
      LAYER via ;
        RECT 12.340 34.730 12.600 34.990 ;
        RECT 12.340 27.170 12.600 27.430 ;
        RECT 12.340 25.070 12.600 25.330 ;
        RECT 11.480 17.930 11.740 18.190 ;
        RECT 8.900 15.830 9.160 16.090 ;
        RECT 11.050 15.830 11.310 16.090 ;
        RECT 11.480 15.830 11.740 16.090 ;
        RECT 8.900 14.570 9.160 14.830 ;
        RECT 11.050 2.810 11.310 3.070 ;
      LAYER met2 ;
        RECT 12.330 25.040 12.610 35.020 ;
        RECT 8.890 14.540 9.170 16.120 ;
        RECT 11.040 2.780 11.320 16.120 ;
        RECT 11.470 15.800 11.750 18.220 ;
  END
END DCDC_MUX
END LIBRARY
